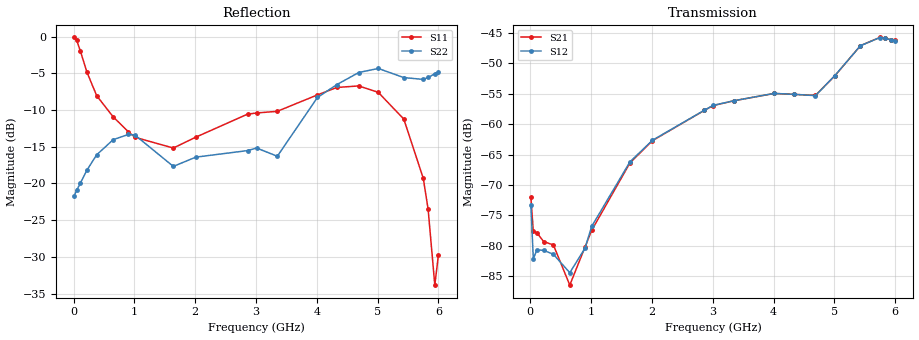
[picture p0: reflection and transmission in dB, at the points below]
!Agilent Technologies,N5230A,MY45001650,A.07.50.48
!Agilent N5230A: A.07.50.48
!Date: Saturday, July 08, 2017 15:53:17
!Correction: S11(Full 2 Port(1,2))
!S21(Full 2 Port(1,2))
!S12(Full 2 Port(1,2))
!S22(Full 2 Port(1,2))
!S2P File: Measurements: S11, S21, S12, S22:
# Hz S  dB  R 50
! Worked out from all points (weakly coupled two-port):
!   600 points, 10 MHz to 6 GHz, reference 50 ohm
!   highest |S21| = -45.72 dB at 5.75 GHz (marker M1); lowest = -86.5 dB at 650 MHz (marker M2)
!   lowest |S11| = -33.8 dB at 5.94 GHz (marker M3), VSWR 1.04, Z = 48.2 - j0.857 ohm
!   |S11| at or under -10 dB: 551.2 MHz to 3.398 GHz (2.846 GHz wide, 144 % of centre); 3.407 GHz to 3.466 GHz (59.32 MHz wide, 1.73 % of centre); 5.331 GHz to end of sweep
!   |S22| runs from -21.7 to -4.3 dB; largest |S21 - S12| = 0.00027
!   S11 on the Smith chart (normalised r, x): 10 MHz: 2, -19; 110 MHz: 0.49, -1.80; 380 MHz: 0.53, -0.41; 2.86 GHz: 0.60, +0.27; 4.33 GHz: 2.52, +0.50; 6 GHz: 0.96, +0.05
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1e7  -0.12 -5.9  -71.99 29.6  -73.24 -40.2  -21.66 -6.5
5e7  -0.51 -27.7  -77.66 108.9  -82.16 37.3  -20.94 -16.1
1.1e8  -1.94 -55.4  -77.89 56.9  -80.69 66.5  -19.97 -35.2
2.2e8  -4.87 -90.5  -79.34 6.8  -80.78 -17.4  -18.18 -63.3
3.8e8  -8.06 -123.6  -79.88 -41.9  -81.42 -40.5  -16.10 -90.3
6.5e8  -10.93 -159.4  -86.50 -128.8  -84.46 -119.5  -14.05 -121.3
9e8  -12.96 -178.3  -80.25 149.8  -80.43 146.5  -13.33 -142.7
1.01e9  -13.72 176.3  -77.48 128.7  -76.84 129.8  -13.42 -153.0
1.64e9  -15.18 170.9  -66.37 47.7  -66.20 47.0  -17.68 167.9
2.01e9  -13.70 172.2  -62.72 5.2  -62.65 5.6  -16.42 158.7
2.86e9  -10.57 136.0  -57.75 -81.7  -57.73 -81.2  -15.53 135.8
3.01e9  -10.41 123.9  -56.94 -98.4  -56.90 -98.2  -15.18 133.1
3.35e9  -10.18 93.2  -56.15 -138.9  -56.15 -139.1  -16.30 149.0
4.01e9  -7.95 29.9  -54.95 159.5  -54.94 159.5  -8.30 158.8
4.33e9  -6.93 10.1  -55.10 129.7  -55.09 129.4  -6.54 149.7
4.69e9  -6.73 -8.3  -55.27 113.1  -55.31 113.3  -4.90 129.3
5.01e9  -7.60 -21.5  -52.03 101.5  -52.00 101.5  -4.35 105.3
5.43e9  -11.24 -41.6  -47.08 56.0  -47.09 56.0  -5.59 75.5
5.75e9  -19.29 -61.3  -45.72 15.5  -45.74 15.7  -5.84 69.0
5.83e9  -23.50 -74.3  -45.82 5.1  -45.82 5.2  -5.57 65.9
5.94e9  -33.84 -154.1  -46.14 -5.2  -46.17 -5.0  -5.08 60.5
6e9  -29.70 131.3  -46.22 -8.9  -46.25 -8.7  -4.87 56.5
